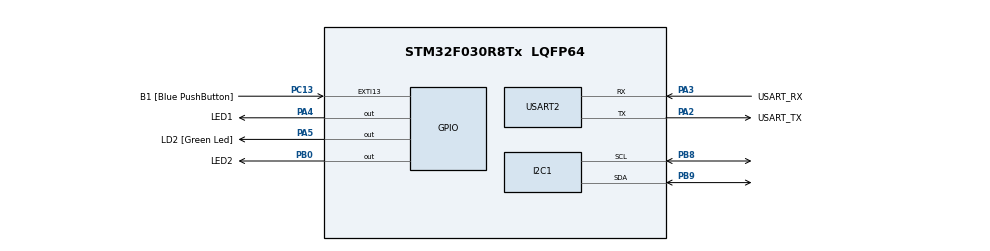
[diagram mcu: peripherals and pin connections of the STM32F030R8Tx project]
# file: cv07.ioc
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FREERTOS.Queues01=xVisualQueue,16,int16_t,0,Dynamic,NULL,NULL
FREERTOS.Tasks01=defaultTask,0,128,StartDefaultTask,Default,NULL,Dynamic,NULL,NULL;VisualTask,-3,128,StartVisualTask,Default,NULL,Dynamic,NULL,NULL;AcceleroTask,-3,128,StartAcceleroTask,Default,NULL,Dynamic,NULL,NULL
Mcu.Family=STM32F0
Mcu.Name=STM32F030R8Tx
Mcu.Package=LQFP64
NVIC.TIM14_IRQn=true\:0\:0\:false\:false\:true\:false\:false\:true
NVIC.TimeBase=TIM14_IRQn
NVIC.TimeBaseIP=TIM14
PA13.GPIO_Label=TMS
PA13.Mode=Serial_Wire
PA13.Signal=SYS_SWDIO
PA14.GPIO_Label=TCK
PA14.Mode=Serial_Wire
PA14.Signal=SYS_SWCLK
PA2.GPIO_Label=USART_TX
PA2.GPIO_Mode=GPIO_MODE_AF_PP
PA2.GPIO_PuPd=GPIO_NOPULL
PA2.GPIO_Speed=GPIO_SPEED_FREQ_LOW
PA2.Mode=Asynchronous
PA2.Signal=USART2_TX
PA3.GPIO_Label=USART_RX
PA3.GPIO_Mode=GPIO_MODE_AF_PP
PA3.GPIO_PuPd=GPIO_NOPULL
PA3.GPIO_Speed=GPIO_SPEED_FREQ_LOW
PA3.Mode=Asynchronous
PA3.Signal=USART2_RX
PA4.GPIO_Label=LED1
PA4.Signal=GPIO_Output
PA5.GPIO_Label=LD2 [Green Led]
PA5.GPIO_Mode=GPIO_MODE_OUTPUT_PP
PA5.GPIO_PuPd=GPIO_NOPULL
PA5.GPIO_Speed=GPIO_SPEED_FREQ_LOW
PA5.Signal=GPIO_Output
PB0.GPIO_Label=LED2
PB0.Signal=GPIO_Output
PB8.Mode=I2C
PB8.Signal=I2C1_SCL
PB9.Mode=I2C
PB9.Signal=I2C1_SDA
PC13.GPIO_Label=B1 [Blue PushButton]
PC13.GPIO_ModeDefaultEXTI=GPIO_MODE_IT_FALLING
PC13.Signal=GPXTI13
PC14-OSC32_IN.Mode=LSE-External-Oscillator
PC14-OSC32_IN.Signal=RCC_OSC32_IN
PC15-OSC32_OUT.Mode=LSE-External-Oscillator
PC15-OSC32_OUT.Signal=RCC_OSC32_OUT
PF0-OSC_IN.Mode=HSE-External-Clock-Source
PF0-OSC_IN.Signal=RCC_OSC_IN
PF1-OSC_OUT.Signal=RCC_OSC_OUT
ProjectManager.HeapSize=0x200
ProjectManager.StackSize=0x400
ProjectManager.TargetToolchain=STM32CubeIDE
RCC.AHBFreq_Value=48000000
RCC.APB1Freq_Value=48000000
RCC.APB1TimFreq_Value=48000000
RCC.HCLKFreq_Value=48000000
RCC.PLLMUL=RCC_PLL_MUL12
RCC.SYSCLKFreq_VALUE=48000000
RCC.SYSCLKSource=RCC_SYSCLKSOURCE_PLLCLK
USART2.VirtualMode-Asynchronous=VM_ASYNC
VP_FREERTOS_VS_CMSIS_V1.Mode=CMSIS_V1
VP_SYS_VS_tim14.Mode=TIM14
board=NUCLEO-F030R8

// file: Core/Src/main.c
/* USER CODE BEGIN Header */
/**
  ******************************************************************************
  * @file           : main.c
  * @brief          : Main program body
  ******************************************************************************
  * @attention
  *
  * <h2><center>&copy; Copyright (c) 2020 STMicroelectronics.
  * All rights reserved.</center></h2>
  *
  * This software component is licensed by ST under BSD 3-Clause license,
  * the "License"; You may not use this file except in compliance with the
  * License. You may obtain a copy of the License at:
  *                        opensource.org/licenses/BSD-3-Clause
  *
  ******************************************************************************
  */
/* USER CODE END Header */
#include "main.h"
#include "cmsis_os.h"

/* USER CODE BEGIN Includes */
#include <stdio.h>
#include "lis2dw12_reg.h"

/* USER CODE END Includes */

I2C_HandleTypeDef hi2c1;

UART_HandleTypeDef huart2;

osThreadId defaultTaskHandle;
osThreadId VisualTaskHandle;
osThreadId AcceleroTaskHandle;
osMessageQId xVisualQueueHandle;

void SystemClock_Config(void);
static void MX_GPIO_Init(void);
static void MX_I2C1_Init(void);
static void MX_USART2_UART_Init(void);
void StartDefaultTask(void const * argument);
void StartVisualTask(void const * argument);
void StartAcceleroTask(void const * argument);

/* USER CODE BEGIN 0 */

static int32_t platform_write(void *handle, uint8_t reg, uint8_t *bufp, uint16_t len);
static int32_t platform_read(void *handle, uint8_t reg, uint8_t *bufp, uint16_t len);
static stmdev_ctx_t lis2dw12 = {
		.write_reg = platform_write,
		.read_reg = platform_read,
		.handle = &hi2c1,
};

/*
 * Replace the functions "platform_write" and "platform_read" with your
 * platform specific read and write function.
 */
static int32_t platform_write(void *handle, uint8_t reg, uint8_t *bufp, uint16_t len)
{
	HAL_I2C_Mem_Write(handle, LIS2DW12_I2C_ADD_H, reg, I2C_MEMADD_SIZE_8BIT, bufp, len, 1000);
	return 0;
}
static int32_t platform_read(void *handle, uint8_t reg, uint8_t *bufp, uint16_t len)
{
	HAL_I2C_Mem_Read(handle, LIS2DW12_I2C_ADD_H, reg, I2C_MEMADD_SIZE_8BIT, bufp, len, 1000);
	return 0;
}

int _write(int file, char const *buf, int n)
{
	/* stdout redirection to UART2 */
	HAL_UART_Transmit(&huart2, (uint8_t*)(buf), n, HAL_MAX_DELAY);
	return n;
}
/* USER CODE END 0 */

int main(void)
{

  /* MCU Configuration--------------------------------------------------------*/

  /* Reset of all peripherals, Initializes the Flash interface and the Systick. */
  HAL_Init();

  /* Configure the system clock */
  SystemClock_Config();

  /* Initialize all configured peripherals */
  MX_GPIO_Init();
  MX_I2C1_Init();
  MX_USART2_UART_Init();

  /* Create the queue(s) */
  /* definition and creation of xVisualQueue */
  osMessageQDef(xVisualQueue, 16, uint16_t);
  xVisualQueueHandle = osMessageCreate(osMessageQ(xVisualQueue), NULL);

  /* Create the thread(s) */
  /* definition and creation of defaultTask */
  osThreadDef(defaultTask, StartDefaultTask, osPriorityNormal, 0, 128);
  defaultTaskHandle = osThreadCreate(osThread(defaultTask), NULL);

  /* definition and creation of VisualTask */
  osThreadDef(VisualTask, StartVisualTask, osPriorityNormal, 0, 128);
  VisualTaskHandle = osThreadCreate(osThread(VisualTask), NULL);

  /* definition and creation of AcceleroTask */
  osThreadDef(AcceleroTask, StartAcceleroTask, osPriorityNormal, 0, 128);
  AcceleroTaskHandle = osThreadCreate(osThread(AcceleroTask), NULL);

  /* Start scheduler */
  osKernelStart();

  /* We should never get here as control is now taken by the scheduler */
  /* Infinite loop */
  while (1)
  {

  }
}

void SystemClock_Config(void)
{
  RCC_OscInitTypeDef RCC_OscInitStruct = {0};
  RCC_ClkInitTypeDef RCC_ClkInitStruct = {0};
  RCC_PeriphCLKInitTypeDef PeriphClkInit = {0};

  /** Initializes the RCC Oscillators according to the specified parameters
  * in the RCC_OscInitTypeDef structure.
  */
   RCC_OscInitStruct.OscillatorType = RCC_OSCILLATORTYPE_HSI;
   RCC_OscInitStruct.HSIState = RCC_HSI_ON;
   RCC_OscInitStruct.PLL.PLLSource = RCC_PLLSOURCE_HSI;
   RCC_OscInitStruct.HSICalibrationValue = RCC_HSICALIBRATION_DEFAULT;
   RCC_OscInitStruct.PLL.PLLState = RCC_PLL_ON;
   RCC_OscInitStruct.PLL.PLLMUL = RCC_PLL_MUL12;
   RCC_OscInitStruct.PLL.PREDIV = RCC_PREDIV_DIV1;
   if (HAL_RCC_OscConfig(&RCC_OscInitStruct) != HAL_OK)
  {
    Error_Handler();
  }
  /** Initializes the CPU, AHB and APB buses clocks
  */
  RCC_ClkInitStruct.ClockType = RCC_CLOCKTYPE_HCLK|RCC_CLOCKTYPE_SYSCLK
                              |RCC_CLOCKTYPE_PCLK1;
  RCC_ClkInitStruct.SYSCLKSource = RCC_SYSCLKSOURCE_HSI;
  RCC_ClkInitStruct.AHBCLKDivider = RCC_SYSCLK_DIV1;
  RCC_ClkInitStruct.APB1CLKDivider = RCC_HCLK_DIV1;

  if (HAL_RCC_ClockConfig(&RCC_ClkInitStruct, FLASH_LATENCY_0) != HAL_OK)
  {
    Error_Handler();
  }
  PeriphClkInit.PeriphClockSelection = RCC_PERIPHCLK_I2C1;
  PeriphClkInit.I2c1ClockSelection = RCC_I2C1CLKSOURCE_HSI;
  if (HAL_RCCEx_PeriphCLKConfig(&PeriphClkInit) != HAL_OK)
  {
    Error_Handler();
  }
}

static void MX_I2C1_Init(void)
{

  hi2c1.Instance = I2C1;
  hi2c1.Init.Timing = 0x2000090E;
  hi2c1.Init.OwnAddress1 = 0;
  hi2c1.Init.AddressingMode = I2C_ADDRESSINGMODE_7BIT;
  hi2c1.Init.DualAddressMode = I2C_DUALADDRESS_DISABLE;
  hi2c1.Init.OwnAddress2 = 0;
  hi2c1.Init.OwnAddress2Masks = I2C_OA2_NOMASK;
  hi2c1.Init.GeneralCallMode = I2C_GENERALCALL_DISABLE;
  hi2c1.Init.NoStretchMode = I2C_NOSTRETCH_DISABLE;
  if (HAL_I2C_Init(&hi2c1) != HAL_OK)
  {
    Error_Handler();
  }
  /** Configure Analogue filter
  */
  if (HAL_I2CEx_ConfigAnalogFilter(&hi2c1, I2C_ANALOGFILTER_ENABLE) != HAL_OK)
  {
    Error_Handler();
  }
  /** Configure Digital filter
  */
  if (HAL_I2CEx_ConfigDigitalFilter(&hi2c1, 0) != HAL_OK)
  {
    Error_Handler();
  }

}

static void MX_USART2_UART_Init(void)
{

  huart2.Instance = USART2;
  huart2.Init.BaudRate = 38400;
  huart2.Init.WordLength = UART_WORDLENGTH_8B;
  huart2.Init.StopBits = UART_STOPBITS_1;
  huart2.Init.Parity = UART_PARITY_NONE;
  huart2.Init.Mode = UART_MODE_TX_RX;
  huart2.Init.HwFlowCtl = UART_HWCONTROL_NONE;
  huart2.Init.OverSampling = UART_OVERSAMPLING_16;
  huart2.Init.OneBitSampling = UART_ONE_BIT_SAMPLE_DISABLE;
  huart2.AdvancedInit.AdvFeatureInit = UART_ADVFEATURE_NO_INIT;
  if (HAL_UART_Init(&huart2) != HAL_OK)
  {
    Error_Handler();
  }

}

static void MX_GPIO_Init(void)
{
  GPIO_InitTypeDef GPIO_InitStruct = {0};

  /* GPIO Ports Clock Enable */
  __HAL_RCC_GPIOC_CLK_ENABLE();
  __HAL_RCC_GPIOF_CLK_ENABLE();
  __HAL_RCC_GPIOA_CLK_ENABLE();
  __HAL_RCC_GPIOB_CLK_ENABLE();
  /*Configure GPIO pin : B1_Pin */
   GPIO_InitStruct.Pin = B1_Pin;
   GPIO_InitStruct.Mode = GPIO_MODE_IT_FALLING;
   GPIO_InitStruct.Pull = GPIO_NOPULL;
   HAL_GPIO_Init(B1_GPIO_Port, &GPIO_InitStruct);

   /*Configure GPIO pins : LED1_Pin LD2_Pin */
   GPIO_InitStruct.Pin = LED1_Pin|LD2_Pin;
   GPIO_InitStruct.Mode = GPIO_MODE_OUTPUT_PP;
   GPIO_InitStruct.Pull = GPIO_NOPULL;
   GPIO_InitStruct.Speed = GPIO_SPEED_FREQ_LOW;
   HAL_GPIO_Init(GPIOA, &GPIO_InitStruct);

   /*Configure GPIO pin : LED2_Pin */
   GPIO_InitStruct.Pin = LED2_Pin;
   GPIO_InitStruct.Mode = GPIO_MODE_OUTPUT_PP;
   GPIO_InitStruct.Pull = GPIO_NOPULL;
   GPIO_InitStruct.Speed = GPIO_SPEED_FREQ_LOW;
   HAL_GPIO_Init(LED2_GPIO_Port, &GPIO_InitStruct);
 }

void StartDefaultTask(void const * argument)
{
  for(;;)
  {
    osDelay(1);
  }
}

void StartVisualTask(void const * argument)
{
  /* USER CODE BEGIN StartVisualTask */
  /* Infinite loop */
	  for(;;)
	  {
		  int16_t msg;  //parametr ktery rozhoduje o rozviceni ledek
		  if (xQueueReceive(xVisualQueueHandle, &msg, portMAX_DELAY)){
			  if (msg < -1000){
			  HAL_GPIO_WritePin(LED1_GPIO_Port, LED1_Pin, GPIO_PIN_SET);  //jestlize je nizsi jak -1000 rozsviti se led1
			  }
			  else{
			  HAL_GPIO_WritePin(LED1_GPIO_Port, LED1_Pin, GPIO_PIN_RESET);  // zhasne led1
			  }

			  if (msg > +1000){
			  HAL_GPIO_WritePin(LED2_GPIO_Port, LED2_Pin, GPIO_PIN_SET);  //podobne pro led2
			  }
			  else{
			  HAL_GPIO_WritePin(LED2_GPIO_Port, LED2_Pin, GPIO_PIN_RESET);
			  }
	  }
	  osDelay(1);
}
  /* USER CODE END StartVisualTask */
}

void StartAcceleroTask(void const * argument)
{
  /* USER CODE BEGIN StartAcceleroTask */
	// Check device ID
	uint8_t c = 0;
	uint8_t whoamI = 0;
	uint8_t samples;
	int16_t raw_acceleration[3];

	lis2dw12_device_id_get(&lis2dw12, &whoamI);
	printf("LIS2DW12_ID %s\n", (whoamI == LIS2DW12_ID) ? "OK" : "FAIL");
	lis2dw12_full_scale_set(&lis2dw12, LIS2DW12_2g);
	lis2dw12_power_mode_set(&lis2dw12, LIS2DW12_CONT_LOW_PWR_LOW_NOISE_2);
	lis2dw12_block_data_update_set(&lis2dw12, PROPERTY_ENABLE);
	lis2dw12_fifo_mode_set(&lis2dw12, LIS2DW12_STREAM_MODE); // enable continuous FIFO
	lis2dw12_data_rate_set(&lis2dw12, LIS2DW12_XL_ODR_25Hz); // enable part from power-down

	/* Infinite loop */
	for(;;) {

		/*const int16_t msg[4] = {-5000, 0, 5000, 0};  //testovaci data
		for (uint16_t i = 0; i < 4; i++) {
			xQueueSend(xVisualQueueHandle, &msg[i], 0);  // v nekonecne smycce se odesilaji data do tasku
			osDelay(300);
		}
		*/

	lis2dw12_fifo_data_level_get(&lis2dw12, &samples);
	c++;
	for (uint8_t i = 0; i < samples; i++) {
		lis2dw12_acceleration_raw_get(&lis2dw12, raw_acceleration);  //precteni dat
	}

	xQueueSend(xVisualQueueHandle, &raw_acceleration[0], 0);
	if (c == 10) {
		c = 0;
		printf("X=%d Y=%d Z=%d\n", raw_acceleration[0], raw_acceleration[1], raw_acceleration[2]);  //vypis dat
	}
	osDelay(50);
}
  /* USER CODE END StartAcceleroTask */
}

void HAL_TIM_PeriodElapsedCallback(TIM_HandleTypeDef *htim)
{
  if (htim->Instance == TIM14) {
    HAL_IncTick();
  }
}

void Error_Handler(void)
{
}

/************************ (C) COPYRIGHT STMicroelectronics *****END OF FILE****/
